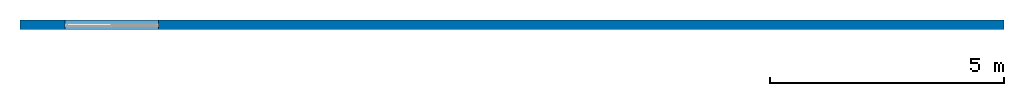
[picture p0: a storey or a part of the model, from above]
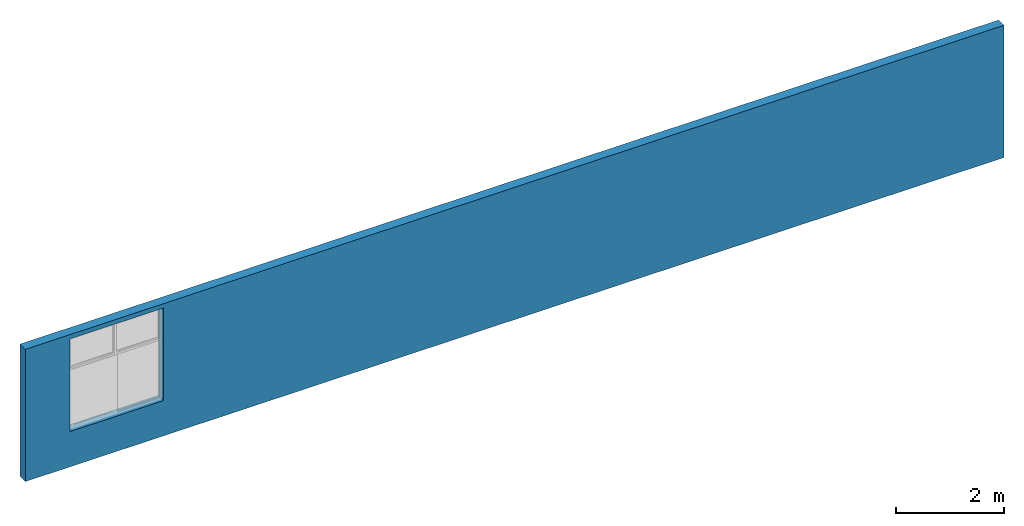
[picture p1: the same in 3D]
Properties of the parts of a building model (IFC2X3)

# File
Description: ViewDefinition [CoordinationView_V2.0], RevitIdentifiers [VersionGUID: 2bd3cde1-d4a2-4600-805d-10032d1099ab, NumberOfSaves: 11], CoordinateReference [CoordinateBase: Shared Coordinates, ProjectSite: Emplazamiento por defecto]
File name: 0001
Time: 2023-11-10T12:01:21-04:00
Author: Scarlett Alday, s.aldayaranda@gmail.com
Written by: ODA SDAI 24.3
Made in: Autodesk Revit 24.1.11.26 (ENU) - IFC 24.1.11.26

# IfcProject, 0001
LongName: Nombre de proyecto; Phase: Estado de proyecto

# IfcSite, Default
RefLatitude: 40, 25, 13, 9643; RefLongitude: -3, -42, -20, -772056; RefElevation: 0 m
Other - Category: Project Information; Client Name: Propietario; Project Address: Introduzca dirección aquí; Project Issue Date: Fecha de emisión; Project Name: Nombre de proyecto; Project Number: 0001; Project Status: Estado de proyecto

# IfcBuilding
Pset_BuildingCommon - NumberOfStoreys: 1
Other - Category: Project Information; Client Name: Propietario; Project Address: Introduzca dirección aquí; Project Issue Date: Fecha de emisión; Project Name: Nombre de proyecto; Project Number: 0001; Project Status: Estado de proyecto

# IfcBuildingStorey: Level:Nivel 1 (2)
Pset_AirSideSystemInformation - sets with these values: 2
Other - Category: Levels; Family: Level; Family and Type: Level: Nivel 1; Type: Nivel 1; Type Id: 927
Dimensions - Computation Height: 0 m
Identity Data - Structural: no; Building Story: yes
Other(Type) - Category: Levels; Family Name: Level
Constraints(Type) - Elevation Base: Project Base Point
Graphics(Type) - Color: 0; Line Pattern: Trazo punto; Line Weight: 1; Symbol: Extremo de nivel; Symbol at End 1 Default: no; Symbol at End 2 Default: yes
Identity Data(Type) - Type Name: Nivel 1
Name | LongName = Pset_AirSideSystemInformation, Name = Identity Data, Name | Elevation (m) = Constraints, Elevation (m)
Nivel 1 | Nivel 1 | 0
Nivel 2 | Nivel 2 | 3

# IfcWallStandardCase: Basic Wall:Por defecto - 20 cm, Basic Wall:Por defecto - 20 cm:162781
In: Nivel 1
Type - PredefinedType: STANDARD; Material: Muro por defecto 0.2 m
Type - Other - Category: Walls; Family Name: Basic Wall
Type - Construction - Function: Exterior; Width: 0.2 m; Wrapping at Inserts: Do not wrap
Type - Graphics - Coarse Scale Fill Color: 0
Type - Identity Data - Keynote: Md.1; Type Name: Por defecto - 20 cm
Type - Analytical Properties - Absorptance: 0.7; Roughness: 3
Type - Pset_WallCommon - IsExternal: yes
Pset_QuantityTakeOff - Reference: Por defecto - 20 cm; sets with these values: 2
Pset_WallCommon - Reference: Por defecto - 20 cm; ExtendToStructure: no; LoadBearing: no
Other - Family: Basic Wall; Family and Type: Basic Wall: Por defecto - 20 cm; Type: Por defecto - 20 cm; Type Id: 16288
Constraints - Base Constraint: Nivel 1; Base Extension Distance: 0 m; Base is Attached: no; Base Offset: 0 m; Location Line: Core Face: Exterior; Related to Mass: no; Room Bounding: yes; Top Constraint: Up to level: Nivel 2; Top Extension Distance: 0 m; Top is Attached: no; Top Offset: 0 m; Unconnected Height: 3 m
Dimensions - Area: 58.8 m2; Length: 21 m; Volume: 11.76 m3
Phasing - Phase Created: Nueva construcción
Structural - Structural: no; Structural Usage: Non-bearing
Cross-Section Definition - Cross-Section: Vertical

# IfcWindow: Deceuninck_Ventana_monorriel_fijo-superior_Bella-Sliding:Deceuninck_Ventana_monorriel_fijo-superior_Bella-Sliding, Deceuninck_Ventana_monorriel_fijo-superior_Bella-Sliding:Deceuninck_Ventana_monorriel_fijo-superior_Bella-Sliding:366877
In: Nivel 1
Type - ParameterTakesPrecedence: no; Sizeable: no; Material: Deceuninck - 1.White/PVC, Glass
Type - Other - Category: Windows; Altura de antepecho por defecto: 0.8 m; Family Name: Deceuninck_Ventana_monorriel_fijo-superior_Bella-Sliding
Type - Model Properties - Air permeability: CLASS 3 - EN14351-1+A1; Water tightness: CLASS 6A - EN14351-1+A1; Wind load resistance: CLASS C3/B4 - EN14351-1+A1
Type - Construction - Wall Closure: By host
Type - Dimensions - Fixed windows Height: 0.7 m; Glass Height: 2.006 m; Glass Width: 1.906 m; Height: 2.1 m; Max. Height: 2.5 m; Max. Width: 2.5 m; Offset: 0.0705 m; Rough Height: 2.032 m; Sash fit: 0.035 m; Width: 2 m
Type - Identity Data - Constructive depth: 73mm; Glazing capacity: 4 - 20mm; Manufacturer: Deceuninck; Model: Sliding; OmniClass Number: 23.30.20.00; OmniClass Title: Windows; Opening: Interior; System: Bella Sliding; Technical Area: info@deceuninckbim.cl; Type Comments: Calculations made based on load of 500 Pa (13km/h); Type Image: Everest Max.png; Type Mark: 58; Type Name: Deceuninck_Ventana_monorriel_fijo-superior_Bella-Sliding; URL: www.deceuninck.cl
Type - Materials and Finishes - Available colours: https://kuula.co/share/collection/7qGbH?logo=1&info=1&fs=1&vr=0&sd=1&thumbs=1; Frame: Deceuninck - 1.White/PVC; Sash: Deceuninck - 1.White/PVC
Type - Structural - Includes reinforcement: yes; Reinforcement: Galvanized steel
Type - Analytical Properties - Analytic Construction: <None>; Define Thermal Properties by: Schematic Type
Type - Pset_ManufacturerTypeInformation - Manufacturer: Deceuninck
Type - Pset_WindowCommon - IsExternal: no
OverallHeight: 2.1 m; OverallWidth: 2 m
Pset_QuantityTakeOff - Reference: Deceuninck_Ventana_monorriel_fijo-superior_Bella-Sliding
Pset_WindowCommon - IsExternal: yes; Reference: Deceuninck_Ventana_monorriel_fijo-superior_Bella-Sliding
Other - Family: Deceuninck_Ventana_monorriel_fijo-superior_Bella-Sliding; Family and Type: Deceuninck_Ventana_monorriel_fijo-superior_Bella-Sliding: Deceuninck_Ventana_monorriel_fijo-superior_Bella-Sliding; Head Height: 2.9 m; Host Id: 162781; ON_OFF - Fixed Height: no; ON_OFF - Height: no; ON_OFF - Width: no; Type: Deceuninck_Ventana_monorriel_fijo-superior_Bella-Sliding; Type Id: 366856
Constraints - Level: Nivel 1; Sill Height: 0.8 m
Dimensions - Area: 9.643 m2; Volume: 0.0706537 m3
Identity Data - Mark: 43
Phasing - Phase Created: Nueva construcción
